VERSION 5.7 ;
BUSBITCHARS "[]" ;
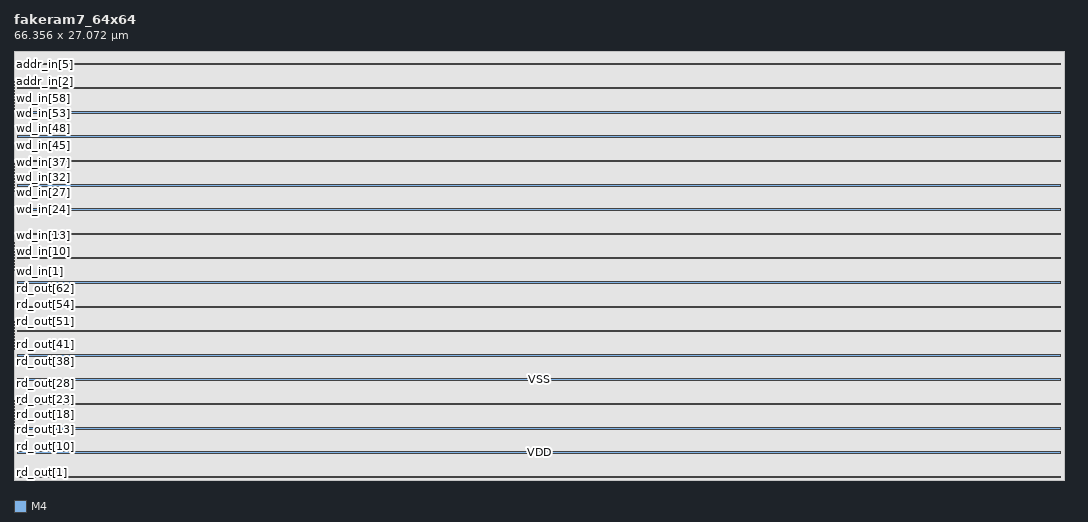
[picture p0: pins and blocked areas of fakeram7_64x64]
MACRO fakeram7_64x64
  FOREIGN fakeram7_64x64 0 0 ;
  SYMMETRY X Y R90 ;
  SIZE 66.356 BY 27.072 ;
  CLASS BLOCK ;
  PIN rd_out[0]
    DIRECTION OUTPUT ;
    USE SIGNAL ;
    SHAPE ABUTMENT ;
    PORT
      LAYER M4 ;
      RECT 0.000 0.192 0.024 0.216 ;
    END
  END rd_out[0]
  PIN rd_out[1]
    DIRECTION OUTPUT ;
    USE SIGNAL ;
    SHAPE ABUTMENT ;
    PORT
      LAYER M4 ;
      RECT 0.000 0.384 0.024 0.408 ;
    END
  END rd_out[1]
  PIN rd_out[2]
    DIRECTION OUTPUT ;
    USE SIGNAL ;
    SHAPE ABUTMENT ;
    PORT
      LAYER M4 ;
      RECT 0.000 0.576 0.024 0.600 ;
    END
  END rd_out[2]
  PIN rd_out[3]
    DIRECTION OUTPUT ;
    USE SIGNAL ;
    SHAPE ABUTMENT ;
    PORT
      LAYER M4 ;
      RECT 0.000 0.768 0.024 0.792 ;
    END
  END rd_out[3]
  PIN rd_out[4]
    DIRECTION OUTPUT ;
    USE SIGNAL ;
    SHAPE ABUTMENT ;
    PORT
      LAYER M4 ;
      RECT 0.000 0.960 0.024 0.984 ;
    END
  END rd_out[4]
  PIN rd_out[5]
    DIRECTION OUTPUT ;
    USE SIGNAL ;
    SHAPE ABUTMENT ;
    PORT
      LAYER M4 ;
      RECT 0.000 1.152 0.024 1.176 ;
    END
  END rd_out[5]
  PIN rd_out[6]
    DIRECTION OUTPUT ;
    USE SIGNAL ;
    SHAPE ABUTMENT ;
    PORT
      LAYER M4 ;
      RECT 0.000 1.344 0.024 1.368 ;
    END
  END rd_out[6]
  PIN rd_out[7]
    DIRECTION OUTPUT ;
    USE SIGNAL ;
    SHAPE ABUTMENT ;
    PORT
      LAYER M4 ;
      RECT 0.000 1.536 0.024 1.560 ;
    END
  END rd_out[7]
  PIN rd_out[8]
    DIRECTION OUTPUT ;
    USE SIGNAL ;
    SHAPE ABUTMENT ;
    PORT
      LAYER M4 ;
      RECT 0.000 1.728 0.024 1.752 ;
    END
  END rd_out[8]
  PIN rd_out[9]
    DIRECTION OUTPUT ;
    USE SIGNAL ;
    SHAPE ABUTMENT ;
    PORT
      LAYER M4 ;
      RECT 0.000 1.920 0.024 1.944 ;
    END
  END rd_out[9]
  PIN rd_out[10]
    DIRECTION OUTPUT ;
    USE SIGNAL ;
    SHAPE ABUTMENT ;
    PORT
      LAYER M4 ;
      RECT 0.000 2.112 0.024 2.136 ;
    END
  END rd_out[10]
  PIN rd_out[11]
    DIRECTION OUTPUT ;
    USE SIGNAL ;
    SHAPE ABUTMENT ;
    PORT
      LAYER M4 ;
      RECT 0.000 2.304 0.024 2.328 ;
    END
  END rd_out[11]
  PIN rd_out[12]
    DIRECTION OUTPUT ;
    USE SIGNAL ;
    SHAPE ABUTMENT ;
    PORT
      LAYER M4 ;
      RECT 0.000 2.496 0.024 2.520 ;
    END
  END rd_out[12]
  PIN rd_out[13]
    DIRECTION OUTPUT ;
    USE SIGNAL ;
    SHAPE ABUTMENT ;
    PORT
      LAYER M4 ;
      RECT 0.000 2.688 0.024 2.712 ;
    END
  END rd_out[13]
  PIN rd_out[14]
    DIRECTION OUTPUT ;
    USE SIGNAL ;
    SHAPE ABUTMENT ;
    PORT
      LAYER M4 ;
      RECT 0.000 2.880 0.024 2.904 ;
    END
  END rd_out[14]
  PIN rd_out[15]
    DIRECTION OUTPUT ;
    USE SIGNAL ;
    SHAPE ABUTMENT ;
    PORT
      LAYER M4 ;
      RECT 0.000 3.072 0.024 3.096 ;
    END
  END rd_out[15]
  PIN rd_out[16]
    DIRECTION OUTPUT ;
    USE SIGNAL ;
    SHAPE ABUTMENT ;
    PORT
      LAYER M4 ;
      RECT 0.000 3.264 0.024 3.288 ;
    END
  END rd_out[16]
  PIN rd_out[17]
    DIRECTION OUTPUT ;
    USE SIGNAL ;
    SHAPE ABUTMENT ;
    PORT
      LAYER M4 ;
      RECT 0.000 3.456 0.024 3.480 ;
    END
  END rd_out[17]
  PIN rd_out[18]
    DIRECTION OUTPUT ;
    USE SIGNAL ;
    SHAPE ABUTMENT ;
    PORT
      LAYER M4 ;
      RECT 0.000 3.648 0.024 3.672 ;
    END
  END rd_out[18]
  PIN rd_out[19]
    DIRECTION OUTPUT ;
    USE SIGNAL ;
    SHAPE ABUTMENT ;
    PORT
      LAYER M4 ;
      RECT 0.000 3.840 0.024 3.864 ;
    END
  END rd_out[19]
  PIN rd_out[20]
    DIRECTION OUTPUT ;
    USE SIGNAL ;
    SHAPE ABUTMENT ;
    PORT
      LAYER M4 ;
      RECT 0.000 4.032 0.024 4.056 ;
    END
  END rd_out[20]
  PIN rd_out[21]
    DIRECTION OUTPUT ;
    USE SIGNAL ;
    SHAPE ABUTMENT ;
    PORT
      LAYER M4 ;
      RECT 0.000 4.224 0.024 4.248 ;
    END
  END rd_out[21]
  PIN rd_out[22]
    DIRECTION OUTPUT ;
    USE SIGNAL ;
    SHAPE ABUTMENT ;
    PORT
      LAYER M4 ;
      RECT 0.000 4.416 0.024 4.440 ;
    END
  END rd_out[22]
  PIN rd_out[23]
    DIRECTION OUTPUT ;
    USE SIGNAL ;
    SHAPE ABUTMENT ;
    PORT
      LAYER M4 ;
      RECT 0.000 4.608 0.024 4.632 ;
    END
  END rd_out[23]
  PIN rd_out[24]
    DIRECTION OUTPUT ;
    USE SIGNAL ;
    SHAPE ABUTMENT ;
    PORT
      LAYER M4 ;
      RECT 0.000 4.800 0.024 4.824 ;
    END
  END rd_out[24]
  PIN rd_out[25]
    DIRECTION OUTPUT ;
    USE SIGNAL ;
    SHAPE ABUTMENT ;
    PORT
      LAYER M4 ;
      RECT 0.000 4.992 0.024 5.016 ;
    END
  END rd_out[25]
  PIN rd_out[26]
    DIRECTION OUTPUT ;
    USE SIGNAL ;
    SHAPE ABUTMENT ;
    PORT
      LAYER M4 ;
      RECT 0.000 5.184 0.024 5.208 ;
    END
  END rd_out[26]
  PIN rd_out[27]
    DIRECTION OUTPUT ;
    USE SIGNAL ;
    SHAPE ABUTMENT ;
    PORT
      LAYER M4 ;
      RECT 0.000 5.376 0.024 5.400 ;
    END
  END rd_out[27]
  PIN rd_out[28]
    DIRECTION OUTPUT ;
    USE SIGNAL ;
    SHAPE ABUTMENT ;
    PORT
      LAYER M4 ;
      RECT 0.000 5.568 0.024 5.592 ;
    END
  END rd_out[28]
  PIN rd_out[29]
    DIRECTION OUTPUT ;
    USE SIGNAL ;
    SHAPE ABUTMENT ;
    PORT
      LAYER M4 ;
      RECT 0.000 5.760 0.024 5.784 ;
    END
  END rd_out[29]
  PIN rd_out[30]
    DIRECTION OUTPUT ;
    USE SIGNAL ;
    SHAPE ABUTMENT ;
    PORT
      LAYER M4 ;
      RECT 0.000 5.952 0.024 5.976 ;
    END
  END rd_out[30]
  PIN rd_out[31]
    DIRECTION OUTPUT ;
    USE SIGNAL ;
    SHAPE ABUTMENT ;
    PORT
      LAYER M4 ;
      RECT 0.000 6.144 0.024 6.168 ;
    END
  END rd_out[31]
  PIN rd_out[32]
    DIRECTION OUTPUT ;
    USE SIGNAL ;
    SHAPE ABUTMENT ;
    PORT
      LAYER M4 ;
      RECT 0.000 6.336 0.024 6.360 ;
    END
  END rd_out[32]
  PIN rd_out[33]
    DIRECTION OUTPUT ;
    USE SIGNAL ;
    SHAPE ABUTMENT ;
    PORT
      LAYER M4 ;
      RECT 0.000 6.528 0.024 6.552 ;
    END
  END rd_out[33]
  PIN rd_out[34]
    DIRECTION OUTPUT ;
    USE SIGNAL ;
    SHAPE ABUTMENT ;
    PORT
      LAYER M4 ;
      RECT 0.000 6.720 0.024 6.744 ;
    END
  END rd_out[34]
  PIN rd_out[35]
    DIRECTION OUTPUT ;
    USE SIGNAL ;
    SHAPE ABUTMENT ;
    PORT
      LAYER M4 ;
      RECT 0.000 6.912 0.024 6.936 ;
    END
  END rd_out[35]
  PIN rd_out[36]
    DIRECTION OUTPUT ;
    USE SIGNAL ;
    SHAPE ABUTMENT ;
    PORT
      LAYER M4 ;
      RECT 0.000 7.104 0.024 7.128 ;
    END
  END rd_out[36]
  PIN rd_out[37]
    DIRECTION OUTPUT ;
    USE SIGNAL ;
    SHAPE ABUTMENT ;
    PORT
      LAYER M4 ;
      RECT 0.000 7.296 0.024 7.320 ;
    END
  END rd_out[37]
  PIN rd_out[38]
    DIRECTION OUTPUT ;
    USE SIGNAL ;
    SHAPE ABUTMENT ;
    PORT
      LAYER M4 ;
      RECT 0.000 7.488 0.024 7.512 ;
    END
  END rd_out[38]
  PIN rd_out[39]
    DIRECTION OUTPUT ;
    USE SIGNAL ;
    SHAPE ABUTMENT ;
    PORT
      LAYER M4 ;
      RECT 0.000 7.680 0.024 7.704 ;
    END
  END rd_out[39]
  PIN rd_out[40]
    DIRECTION OUTPUT ;
    USE SIGNAL ;
    SHAPE ABUTMENT ;
    PORT
      LAYER M4 ;
      RECT 0.000 7.872 0.024 7.896 ;
    END
  END rd_out[40]
  PIN rd_out[41]
    DIRECTION OUTPUT ;
    USE SIGNAL ;
    SHAPE ABUTMENT ;
    PORT
      LAYER M4 ;
      RECT 0.000 8.064 0.024 8.088 ;
    END
  END rd_out[41]
  PIN rd_out[42]
    DIRECTION OUTPUT ;
    USE SIGNAL ;
    SHAPE ABUTMENT ;
    PORT
      LAYER M4 ;
      RECT 0.000 8.256 0.024 8.280 ;
    END
  END rd_out[42]
  PIN rd_out[43]
    DIRECTION OUTPUT ;
    USE SIGNAL ;
    SHAPE ABUTMENT ;
    PORT
      LAYER M4 ;
      RECT 0.000 8.448 0.024 8.472 ;
    END
  END rd_out[43]
  PIN rd_out[44]
    DIRECTION OUTPUT ;
    USE SIGNAL ;
    SHAPE ABUTMENT ;
    PORT
      LAYER M4 ;
      RECT 0.000 8.640 0.024 8.664 ;
    END
  END rd_out[44]
  PIN rd_out[45]
    DIRECTION OUTPUT ;
    USE SIGNAL ;
    SHAPE ABUTMENT ;
    PORT
      LAYER M4 ;
      RECT 0.000 8.832 0.024 8.856 ;
    END
  END rd_out[45]
  PIN rd_out[46]
    DIRECTION OUTPUT ;
    USE SIGNAL ;
    SHAPE ABUTMENT ;
    PORT
      LAYER M4 ;
      RECT 0.000 9.024 0.024 9.048 ;
    END
  END rd_out[46]
  PIN rd_out[47]
    DIRECTION OUTPUT ;
    USE SIGNAL ;
    SHAPE ABUTMENT ;
    PORT
      LAYER M4 ;
      RECT 0.000 9.216 0.024 9.240 ;
    END
  END rd_out[47]
  PIN rd_out[48]
    DIRECTION OUTPUT ;
    USE SIGNAL ;
    SHAPE ABUTMENT ;
    PORT
      LAYER M4 ;
      RECT 0.000 9.408 0.024 9.432 ;
    END
  END rd_out[48]
  PIN rd_out[49]
    DIRECTION OUTPUT ;
    USE SIGNAL ;
    SHAPE ABUTMENT ;
    PORT
      LAYER M4 ;
      RECT 0.000 9.600 0.024 9.624 ;
    END
  END rd_out[49]
  PIN rd_out[50]
    DIRECTION OUTPUT ;
    USE SIGNAL ;
    SHAPE ABUTMENT ;
    PORT
      LAYER M4 ;
      RECT 0.000 9.792 0.024 9.816 ;
    END
  END rd_out[50]
  PIN rd_out[51]
    DIRECTION OUTPUT ;
    USE SIGNAL ;
    SHAPE ABUTMENT ;
    PORT
      LAYER M4 ;
      RECT 0.000 9.984 0.024 10.008 ;
    END
  END rd_out[51]
  PIN rd_out[52]
    DIRECTION OUTPUT ;
    USE SIGNAL ;
    SHAPE ABUTMENT ;
    PORT
      LAYER M4 ;
      RECT 0.000 10.176 0.024 10.200 ;
    END
  END rd_out[52]
  PIN rd_out[53]
    DIRECTION OUTPUT ;
    USE SIGNAL ;
    SHAPE ABUTMENT ;
    PORT
      LAYER M4 ;
      RECT 0.000 10.368 0.024 10.392 ;
    END
  END rd_out[53]
  PIN rd_out[54]
    DIRECTION OUTPUT ;
    USE SIGNAL ;
    SHAPE ABUTMENT ;
    PORT
      LAYER M4 ;
      RECT 0.000 10.560 0.024 10.584 ;
    END
  END rd_out[54]
  PIN rd_out[55]
    DIRECTION OUTPUT ;
    USE SIGNAL ;
    SHAPE ABUTMENT ;
    PORT
      LAYER M4 ;
      RECT 0.000 10.752 0.024 10.776 ;
    END
  END rd_out[55]
  PIN rd_out[56]
    DIRECTION OUTPUT ;
    USE SIGNAL ;
    SHAPE ABUTMENT ;
    PORT
      LAYER M4 ;
      RECT 0.000 10.944 0.024 10.968 ;
    END
  END rd_out[56]
  PIN rd_out[57]
    DIRECTION OUTPUT ;
    USE SIGNAL ;
    SHAPE ABUTMENT ;
    PORT
      LAYER M4 ;
      RECT 0.000 11.136 0.024 11.160 ;
    END
  END rd_out[57]
  PIN rd_out[58]
    DIRECTION OUTPUT ;
    USE SIGNAL ;
    SHAPE ABUTMENT ;
    PORT
      LAYER M4 ;
      RECT 0.000 11.328 0.024 11.352 ;
    END
  END rd_out[58]
  PIN rd_out[59]
    DIRECTION OUTPUT ;
    USE SIGNAL ;
    SHAPE ABUTMENT ;
    PORT
      LAYER M4 ;
      RECT 0.000 11.520 0.024 11.544 ;
    END
  END rd_out[59]
  PIN rd_out[60]
    DIRECTION OUTPUT ;
    USE SIGNAL ;
    SHAPE ABUTMENT ;
    PORT
      LAYER M4 ;
      RECT 0.000 11.712 0.024 11.736 ;
    END
  END rd_out[60]
  PIN rd_out[61]
    DIRECTION OUTPUT ;
    USE SIGNAL ;
    SHAPE ABUTMENT ;
    PORT
      LAYER M4 ;
      RECT 0.000 11.904 0.024 11.928 ;
    END
  END rd_out[61]
  PIN rd_out[62]
    DIRECTION OUTPUT ;
    USE SIGNAL ;
    SHAPE ABUTMENT ;
    PORT
      LAYER M4 ;
      RECT 0.000 12.096 0.024 12.120 ;
    END
  END rd_out[62]
  PIN rd_out[63]
    DIRECTION OUTPUT ;
    USE SIGNAL ;
    SHAPE ABUTMENT ;
    PORT
      LAYER M4 ;
      RECT 0.000 12.288 0.024 12.312 ;
    END
  END rd_out[63]
  PIN wd_in[0]
    DIRECTION INPUT ;
    USE SIGNAL ;
    SHAPE ABUTMENT ;
    PORT
      LAYER M4 ;
      RECT 0.000 12.480 0.024 12.504 ;
    END
  END wd_in[0]
  PIN wd_in[1]
    DIRECTION INPUT ;
    USE SIGNAL ;
    SHAPE ABUTMENT ;
    PORT
      LAYER M4 ;
      RECT 0.000 12.672 0.024 12.696 ;
    END
  END wd_in[1]
  PIN wd_in[2]
    DIRECTION INPUT ;
    USE SIGNAL ;
    SHAPE ABUTMENT ;
    PORT
      LAYER M4 ;
      RECT 0.000 12.864 0.024 12.888 ;
    END
  END wd_in[2]
  PIN wd_in[3]
    DIRECTION INPUT ;
    USE SIGNAL ;
    SHAPE ABUTMENT ;
    PORT
      LAYER M4 ;
      RECT 0.000 13.056 0.024 13.080 ;
    END
  END wd_in[3]
  PIN wd_in[4]
    DIRECTION INPUT ;
    USE SIGNAL ;
    SHAPE ABUTMENT ;
    PORT
      LAYER M4 ;
      RECT 0.000 13.248 0.024 13.272 ;
    END
  END wd_in[4]
  PIN wd_in[5]
    DIRECTION INPUT ;
    USE SIGNAL ;
    SHAPE ABUTMENT ;
    PORT
      LAYER M4 ;
      RECT 0.000 13.440 0.024 13.464 ;
    END
  END wd_in[5]
  PIN wd_in[6]
    DIRECTION INPUT ;
    USE SIGNAL ;
    SHAPE ABUTMENT ;
    PORT
      LAYER M4 ;
      RECT 0.000 13.632 0.024 13.656 ;
    END
  END wd_in[6]
  PIN wd_in[7]
    DIRECTION INPUT ;
    USE SIGNAL ;
    SHAPE ABUTMENT ;
    PORT
      LAYER M4 ;
      RECT 0.000 13.824 0.024 13.848 ;
    END
  END wd_in[7]
  PIN wd_in[8]
    DIRECTION INPUT ;
    USE SIGNAL ;
    SHAPE ABUTMENT ;
    PORT
      LAYER M4 ;
      RECT 0.000 14.016 0.024 14.040 ;
    END
  END wd_in[8]
  PIN wd_in[9]
    DIRECTION INPUT ;
    USE SIGNAL ;
    SHAPE ABUTMENT ;
    PORT
      LAYER M4 ;
      RECT 0.000 14.208 0.024 14.232 ;
    END
  END wd_in[9]
  PIN wd_in[10]
    DIRECTION INPUT ;
    USE SIGNAL ;
    SHAPE ABUTMENT ;
    PORT
      LAYER M4 ;
      RECT 0.000 14.400 0.024 14.424 ;
    END
  END wd_in[10]
  PIN wd_in[11]
    DIRECTION INPUT ;
    USE SIGNAL ;
    SHAPE ABUTMENT ;
    PORT
      LAYER M4 ;
      RECT 0.000 14.592 0.024 14.616 ;
    END
  END wd_in[11]
  PIN wd_in[12]
    DIRECTION INPUT ;
    USE SIGNAL ;
    SHAPE ABUTMENT ;
    PORT
      LAYER M4 ;
      RECT 0.000 14.784 0.024 14.808 ;
    END
  END wd_in[12]
  PIN wd_in[13]
    DIRECTION INPUT ;
    USE SIGNAL ;
    SHAPE ABUTMENT ;
    PORT
      LAYER M4 ;
      RECT 0.000 14.976 0.024 15.000 ;
    END
  END wd_in[13]
  PIN wd_in[14]
    DIRECTION INPUT ;
    USE SIGNAL ;
    SHAPE ABUTMENT ;
    PORT
      LAYER M4 ;
      RECT 0.000 15.168 0.024 15.192 ;
    END
  END wd_in[14]
  PIN wd_in[15]
    DIRECTION INPUT ;
    USE SIGNAL ;
    SHAPE ABUTMENT ;
    PORT
      LAYER M4 ;
      RECT 0.000 15.360 0.024 15.384 ;
    END
  END wd_in[15]
  PIN wd_in[16]
    DIRECTION INPUT ;
    USE SIGNAL ;
    SHAPE ABUTMENT ;
    PORT
      LAYER M4 ;
      RECT 0.000 15.552 0.024 15.576 ;
    END
  END wd_in[16]
  PIN wd_in[17]
    DIRECTION INPUT ;
    USE SIGNAL ;
    SHAPE ABUTMENT ;
    PORT
      LAYER M4 ;
      RECT 0.000 15.744 0.024 15.768 ;
    END
  END wd_in[17]
  PIN wd_in[18]
    DIRECTION INPUT ;
    USE SIGNAL ;
    SHAPE ABUTMENT ;
    PORT
      LAYER M4 ;
      RECT 0.000 15.936 0.024 15.960 ;
    END
  END wd_in[18]
  PIN wd_in[19]
    DIRECTION INPUT ;
    USE SIGNAL ;
    SHAPE ABUTMENT ;
    PORT
      LAYER M4 ;
      RECT 0.000 16.128 0.024 16.152 ;
    END
  END wd_in[19]
  PIN wd_in[20]
    DIRECTION INPUT ;
    USE SIGNAL ;
    SHAPE ABUTMENT ;
    PORT
      LAYER M4 ;
      RECT 0.000 16.320 0.024 16.344 ;
    END
  END wd_in[20]
  PIN wd_in[21]
    DIRECTION INPUT ;
    USE SIGNAL ;
    SHAPE ABUTMENT ;
    PORT
      LAYER M4 ;
      RECT 0.000 16.512 0.024 16.536 ;
    END
  END wd_in[21]
  PIN wd_in[22]
    DIRECTION INPUT ;
    USE SIGNAL ;
    SHAPE ABUTMENT ;
    PORT
      LAYER M4 ;
      RECT 0.000 16.704 0.024 16.728 ;
    END
  END wd_in[22]
  PIN wd_in[23]
    DIRECTION INPUT ;
    USE SIGNAL ;
    SHAPE ABUTMENT ;
    PORT
      LAYER M4 ;
      RECT 0.000 16.896 0.024 16.920 ;
    END
  END wd_in[23]
  PIN wd_in[24]
    DIRECTION INPUT ;
    USE SIGNAL ;
    SHAPE ABUTMENT ;
    PORT
      LAYER M4 ;
      RECT 0.000 17.088 0.024 17.112 ;
    END
  END wd_in[24]
  PIN wd_in[25]
    DIRECTION INPUT ;
    USE SIGNAL ;
    SHAPE ABUTMENT ;
    PORT
      LAYER M4 ;
      RECT 0.000 17.280 0.024 17.304 ;
    END
  END wd_in[25]
  PIN wd_in[26]
    DIRECTION INPUT ;
    USE SIGNAL ;
    SHAPE ABUTMENT ;
    PORT
      LAYER M4 ;
      RECT 0.000 17.472 0.024 17.496 ;
    END
  END wd_in[26]
  PIN wd_in[27]
    DIRECTION INPUT ;
    USE SIGNAL ;
    SHAPE ABUTMENT ;
    PORT
      LAYER M4 ;
      RECT 0.000 17.664 0.024 17.688 ;
    END
  END wd_in[27]
  PIN wd_in[28]
    DIRECTION INPUT ;
    USE SIGNAL ;
    SHAPE ABUTMENT ;
    PORT
      LAYER M4 ;
      RECT 0.000 17.856 0.024 17.880 ;
    END
  END wd_in[28]
  PIN wd_in[29]
    DIRECTION INPUT ;
    USE SIGNAL ;
    SHAPE ABUTMENT ;
    PORT
      LAYER M4 ;
      RECT 0.000 18.048 0.024 18.072 ;
    END
  END wd_in[29]
  PIN wd_in[30]
    DIRECTION INPUT ;
    USE SIGNAL ;
    SHAPE ABUTMENT ;
    PORT
      LAYER M4 ;
      RECT 0.000 18.240 0.024 18.264 ;
    END
  END wd_in[30]
  PIN wd_in[31]
    DIRECTION INPUT ;
    USE SIGNAL ;
    SHAPE ABUTMENT ;
    PORT
      LAYER M4 ;
      RECT 0.000 18.432 0.024 18.456 ;
    END
  END wd_in[31]
  PIN wd_in[32]
    DIRECTION INPUT ;
    USE SIGNAL ;
    SHAPE ABUTMENT ;
    PORT
      LAYER M4 ;
      RECT 0.000 18.624 0.024 18.648 ;
    END
  END wd_in[32]
  PIN wd_in[33]
    DIRECTION INPUT ;
    USE SIGNAL ;
    SHAPE ABUTMENT ;
    PORT
      LAYER M4 ;
      RECT 0.000 18.816 0.024 18.840 ;
    END
  END wd_in[33]
  PIN wd_in[34]
    DIRECTION INPUT ;
    USE SIGNAL ;
    SHAPE ABUTMENT ;
    PORT
      LAYER M4 ;
      RECT 0.000 19.008 0.024 19.032 ;
    END
  END wd_in[34]
  PIN wd_in[35]
    DIRECTION INPUT ;
    USE SIGNAL ;
    SHAPE ABUTMENT ;
    PORT
      LAYER M4 ;
      RECT 0.000 19.200 0.024 19.224 ;
    END
  END wd_in[35]
  PIN wd_in[36]
    DIRECTION INPUT ;
    USE SIGNAL ;
    SHAPE ABUTMENT ;
    PORT
      LAYER M4 ;
      RECT 0.000 19.392 0.024 19.416 ;
    END
  END wd_in[36]
  PIN wd_in[37]
    DIRECTION INPUT ;
    USE SIGNAL ;
    SHAPE ABUTMENT ;
    PORT
      LAYER M4 ;
      RECT 0.000 19.584 0.024 19.608 ;
    END
  END wd_in[37]
  PIN wd_in[38]
    DIRECTION INPUT ;
    USE SIGNAL ;
    SHAPE ABUTMENT ;
    PORT
      LAYER M4 ;
      RECT 0.000 19.776 0.024 19.800 ;
    END
  END wd_in[38]
  PIN wd_in[39]
    DIRECTION INPUT ;
    USE SIGNAL ;
    SHAPE ABUTMENT ;
    PORT
      LAYER M4 ;
      RECT 0.000 19.968 0.024 19.992 ;
    END
  END wd_in[39]
  PIN wd_in[40]
    DIRECTION INPUT ;
    USE SIGNAL ;
    SHAPE ABUTMENT ;
    PORT
      LAYER M4 ;
      RECT 0.000 20.160 0.024 20.184 ;
    END
  END wd_in[40]
  PIN wd_in[41]
    DIRECTION INPUT ;
    USE SIGNAL ;
    SHAPE ABUTMENT ;
    PORT
      LAYER M4 ;
      RECT 0.000 20.352 0.024 20.376 ;
    END
  END wd_in[41]
  PIN wd_in[42]
    DIRECTION INPUT ;
    USE SIGNAL ;
    SHAPE ABUTMENT ;
    PORT
      LAYER M4 ;
      RECT 0.000 20.544 0.024 20.568 ;
    END
  END wd_in[42]
  PIN wd_in[43]
    DIRECTION INPUT ;
    USE SIGNAL ;
    SHAPE ABUTMENT ;
    PORT
      LAYER M4 ;
      RECT 0.000 20.736 0.024 20.760 ;
    END
  END wd_in[43]
  PIN wd_in[44]
    DIRECTION INPUT ;
    USE SIGNAL ;
    SHAPE ABUTMENT ;
    PORT
      LAYER M4 ;
      RECT 0.000 20.928 0.024 20.952 ;
    END
  END wd_in[44]
  PIN wd_in[45]
    DIRECTION INPUT ;
    USE SIGNAL ;
    SHAPE ABUTMENT ;
    PORT
      LAYER M4 ;
      RECT 0.000 21.120 0.024 21.144 ;
    END
  END wd_in[45]
  PIN wd_in[46]
    DIRECTION INPUT ;
    USE SIGNAL ;
    SHAPE ABUTMENT ;
    PORT
      LAYER M4 ;
      RECT 0.000 21.312 0.024 21.336 ;
    END
  END wd_in[46]
  PIN wd_in[47]
    DIRECTION INPUT ;
    USE SIGNAL ;
    SHAPE ABUTMENT ;
    PORT
      LAYER M4 ;
      RECT 0.000 21.504 0.024 21.528 ;
    END
  END wd_in[47]
  PIN wd_in[48]
    DIRECTION INPUT ;
    USE SIGNAL ;
    SHAPE ABUTMENT ;
    PORT
      LAYER M4 ;
      RECT 0.000 21.696 0.024 21.720 ;
    END
  END wd_in[48]
  PIN wd_in[49]
    DIRECTION INPUT ;
    USE SIGNAL ;
    SHAPE ABUTMENT ;
    PORT
      LAYER M4 ;
      RECT 0.000 21.888 0.024 21.912 ;
    END
  END wd_in[49]
  PIN wd_in[50]
    DIRECTION INPUT ;
    USE SIGNAL ;
    SHAPE ABUTMENT ;
    PORT
      LAYER M4 ;
      RECT 0.000 22.080 0.024 22.104 ;
    END
  END wd_in[50]
  PIN wd_in[51]
    DIRECTION INPUT ;
    USE SIGNAL ;
    SHAPE ABUTMENT ;
    PORT
      LAYER M4 ;
      RECT 0.000 22.272 0.024 22.296 ;
    END
  END wd_in[51]
  PIN wd_in[52]
    DIRECTION INPUT ;
    USE SIGNAL ;
    SHAPE ABUTMENT ;
    PORT
      LAYER M4 ;
      RECT 0.000 22.464 0.024 22.488 ;
    END
  END wd_in[52]
  PIN wd_in[53]
    DIRECTION INPUT ;
    USE SIGNAL ;
    SHAPE ABUTMENT ;
    PORT
      LAYER M4 ;
      RECT 0.000 22.656 0.024 22.680 ;
    END
  END wd_in[53]
  PIN wd_in[54]
    DIRECTION INPUT ;
    USE SIGNAL ;
    SHAPE ABUTMENT ;
    PORT
      LAYER M4 ;
      RECT 0.000 22.848 0.024 22.872 ;
    END
  END wd_in[54]
  PIN wd_in[55]
    DIRECTION INPUT ;
    USE SIGNAL ;
    SHAPE ABUTMENT ;
    PORT
      LAYER M4 ;
      RECT 0.000 23.040 0.024 23.064 ;
    END
  END wd_in[55]
  PIN wd_in[56]
    DIRECTION INPUT ;
    USE SIGNAL ;
    SHAPE ABUTMENT ;
    PORT
      LAYER M4 ;
      RECT 0.000 23.232 0.024 23.256 ;
    END
  END wd_in[56]
  PIN wd_in[57]
    DIRECTION INPUT ;
    USE SIGNAL ;
    SHAPE ABUTMENT ;
    PORT
      LAYER M4 ;
      RECT 0.000 23.424 0.024 23.448 ;
    END
  END wd_in[57]
  PIN wd_in[58]
    DIRECTION INPUT ;
    USE SIGNAL ;
    SHAPE ABUTMENT ;
    PORT
      LAYER M4 ;
      RECT 0.000 23.616 0.024 23.640 ;
    END
  END wd_in[58]
  PIN wd_in[59]
    DIRECTION INPUT ;
    USE SIGNAL ;
    SHAPE ABUTMENT ;
    PORT
      LAYER M4 ;
      RECT 0.000 23.808 0.024 23.832 ;
    END
  END wd_in[59]
  PIN wd_in[60]
    DIRECTION INPUT ;
    USE SIGNAL ;
    SHAPE ABUTMENT ;
    PORT
      LAYER M4 ;
      RECT 0.000 24.000 0.024 24.024 ;
    END
  END wd_in[60]
  PIN wd_in[61]
    DIRECTION INPUT ;
    USE SIGNAL ;
    SHAPE ABUTMENT ;
    PORT
      LAYER M4 ;
      RECT 0.000 24.192 0.024 24.216 ;
    END
  END wd_in[61]
  PIN wd_in[62]
    DIRECTION INPUT ;
    USE SIGNAL ;
    SHAPE ABUTMENT ;
    PORT
      LAYER M4 ;
      RECT 0.000 24.384 0.024 24.408 ;
    END
  END wd_in[62]
  PIN wd_in[63]
    DIRECTION INPUT ;
    USE SIGNAL ;
    SHAPE ABUTMENT ;
    PORT
      LAYER M4 ;
      RECT 0.000 24.576 0.024 24.600 ;
    END
  END wd_in[63]
  PIN addr_in[0]
    DIRECTION INPUT ;
    USE SIGNAL ;
    SHAPE ABUTMENT ;
    PORT
      LAYER M4 ;
      RECT 0.000 24.768 0.024 24.792 ;
    END
  END addr_in[0]
  PIN addr_in[1]
    DIRECTION INPUT ;
    USE SIGNAL ;
    SHAPE ABUTMENT ;
    PORT
      LAYER M4 ;
      RECT 0.000 24.960 0.024 24.984 ;
    END
  END addr_in[1]
  PIN addr_in[2]
    DIRECTION INPUT ;
    USE SIGNAL ;
    SHAPE ABUTMENT ;
    PORT
      LAYER M4 ;
      RECT 0.000 25.152 0.024 25.176 ;
    END
  END addr_in[2]
  PIN addr_in[3]
    DIRECTION INPUT ;
    USE SIGNAL ;
    SHAPE ABUTMENT ;
    PORT
      LAYER M4 ;
      RECT 0.000 25.344 0.024 25.368 ;
    END
  END addr_in[3]
  PIN addr_in[4]
    DIRECTION INPUT ;
    USE SIGNAL ;
    SHAPE ABUTMENT ;
    PORT
      LAYER M4 ;
      RECT 0.000 25.536 0.024 25.560 ;
    END
  END addr_in[4]
  PIN addr_in[5]
    DIRECTION INPUT ;
    USE SIGNAL ;
    SHAPE ABUTMENT ;
    PORT
      LAYER M4 ;
      RECT 0.000 25.728 0.024 25.752 ;
    END
  END addr_in[5]
  PIN we_in
    DIRECTION INPUT ;
    USE SIGNAL ;
    SHAPE ABUTMENT ;
    PORT
      LAYER M4 ;
      RECT 0.000 25.920 0.024 25.944 ;
    END
  END we_in
  PIN ce_in
    DIRECTION INPUT ;
    USE SIGNAL ;
    SHAPE ABUTMENT ;
    PORT
      LAYER M4 ;
      RECT 0.000 26.112 0.024 26.136 ;
    END
  END ce_in
  PIN clk
    DIRECTION INPUT ;
    USE SIGNAL ;
    SHAPE ABUTMENT ;
    PORT
      LAYER M4 ;
      RECT 0.000 26.304 0.024 26.328 ;
    END
  END clk
  PIN VSS
    DIRECTION INOUT ;
    USE GROUND ;
    PORT
      LAYER M4 ;
      RECT 0.192 0.144 66.164 0.240 ;
      RECT 0.192 3.216 66.164 3.312 ;
      RECT 0.192 6.288 66.164 6.384 ;
      RECT 0.192 9.360 66.164 9.456 ;
      RECT 0.192 12.432 66.164 12.528 ;
      RECT 0.192 15.504 66.164 15.600 ;
      RECT 0.192 18.576 66.164 18.672 ;
      RECT 0.192 21.648 66.164 21.744 ;
      RECT 0.192 24.720 66.164 24.816 ;
    END
  END VSS
  PIN VDD
    DIRECTION INOUT ;
    USE POWER ;
    PORT
      LAYER M4 ;
      RECT 0.192 1.680 66.164 1.776 ;
      RECT 0.192 4.752 66.164 4.848 ;
      RECT 0.192 7.824 66.164 7.920 ;
      RECT 0.192 10.896 66.164 10.992 ;
      RECT 0.192 13.968 66.164 14.064 ;
      RECT 0.192 17.040 66.164 17.136 ;
      RECT 0.192 20.112 66.164 20.208 ;
      RECT 0.192 23.184 66.164 23.280 ;
      RECT 0.192 26.256 66.164 26.352 ;
    END
  END VDD
  OBS
    LAYER M1 ;
    RECT 0 0 66.356 27.072 ;
    LAYER M2 ;
    RECT 0 0 66.356 27.072 ;
    LAYER M3 ;
    RECT 0 0 66.356 27.072 ;
    LAYER M4 ;
    RECT 0 0 66.356 27.072 ;
  END
END fakeram7_64x64

END LIBRARY
